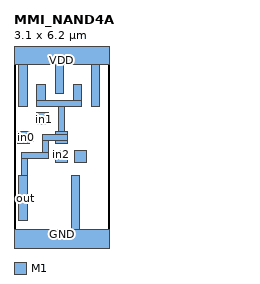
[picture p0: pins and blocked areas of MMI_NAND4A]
MACRO MMI_NAND4A
	CLASS CORE ;
	FOREIGN MMI_NAND4A 0 0 ;
	SIZE 3.1 BY 6.2 ;
	SYMMETRY X Y ;
	SITE CORE1 ;
	PIN out
		DIRECTION output ;
		USE SIGNAL ;
		PORT
			LAYER M1 ;
			RECT 0.75 4.625 1.03 5.135 ;
			LAYER M1 ;
			RECT 1.93 4.625 2.21 5.135 ;
			LAYER M1 ;
			RECT 0.75 4.435 2.21 4.625 ;
			LAYER M1 ;
			RECT 1.44 3.6 1.635 4.435 ;
			LAYER M1 ;
			RECT 1.36 3.505 1.74 3.6 ;
			LAYER M1 ;
			RECT 0.92 3.315 1.74 3.505 ;
			LAYER M1 ;
			RECT 0.92 2.93 1.115 3.315 ;
			LAYER M1 ;
			RECT 1.36 3.22 1.74 3.315 ;
			LAYER M1 ;
			RECT 0.245 2.735 1.115 2.93 ;
			LAYER M1 ;
			RECT 0.245 2.165 0.435 2.735 ;
			LAYER M1 ;
			RECT 0.16 0.695 0.44 2.165 ;
		END
		AntennaDiffArea 1.2859 ;
	END out
	PIN in1
		DIRECTION input ;
		USE SIGNAL ;
		PORT
			LAYER M1 ;
			RECT 0.74 4.13 1.12 4.22 ;
			LAYER M1 ;
			RECT 0.74 3.85 1.205 4.13 ;
			LAYER M1 ;
			RECT 0.74 3.84 1.12 3.85 ;
		END
		AntennaGateArea 0.3465 ;
	END in1
	PIN GND
		DIRECTION inout ;
		USE GROUND ;
		PORT
			LAYER M1 ;
			RECT 1.86 0.42 2.14 2.165 ;
			LAYER M1 ;
			RECT 0 -0.42 3.1 0.42 ;
		END
	END GND
	PIN in2
		DIRECTION input ;
		USE SIGNAL ;
		PORT
			LAYER M1 ;
			RECT 1.32 2.7 1.74 2.98 ;
			LAYER M1 ;
			RECT 1.36 2.6 1.74 2.7 ;
		END
		AntennaGateArea 0.3465 ;
	END in2
	PIN VDD
		DIRECTION inout ;
		USE POWER ;
		PORT
			LAYER M1 ;
			RECT 0 5.78 3.1 6.62 ;
			LAYER M1 ;
			RECT 0.16 4.435 0.44 5.78 ;
			LAYER M1 ;
			RECT 1.34 4.855 1.62 5.78 ;
			LAYER M1 ;
			RECT 2.52 4.435 2.8 5.78 ;
		END
	END VDD
	PIN in3
		DIRECTION input ;
		USE SIGNAL ;
		PORT
			LAYER M1 ;
			RECT 1.98 2.6 2.36 2.98 ;
		END
		AntennaGateArea 0.3465 ;
	END in3
	PIN in0
		DIRECTION input ;
		USE SIGNAL ;
		PORT
			LAYER M1 ;
			RECT 0.12 3.55 0.5 3.6 ;
			LAYER M1 ;
			RECT 0.12 3.27 0.635 3.55 ;
			LAYER M1 ;
			RECT 0.12 3.22 0.5 3.27 ;
		END
		AntennaGateArea 0.3465 ;
	END in0
	OBS
	END
END MMI_NAND4A
